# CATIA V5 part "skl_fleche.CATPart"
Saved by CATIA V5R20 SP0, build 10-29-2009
Part number: skl_fleche
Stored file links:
  D:\IFMA\COURS\2A\Semestre 3\IAO\projet balance\skl_fleche.CATPart

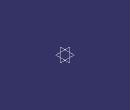
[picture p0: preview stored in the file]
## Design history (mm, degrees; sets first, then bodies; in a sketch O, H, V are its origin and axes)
Body1 (main body)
